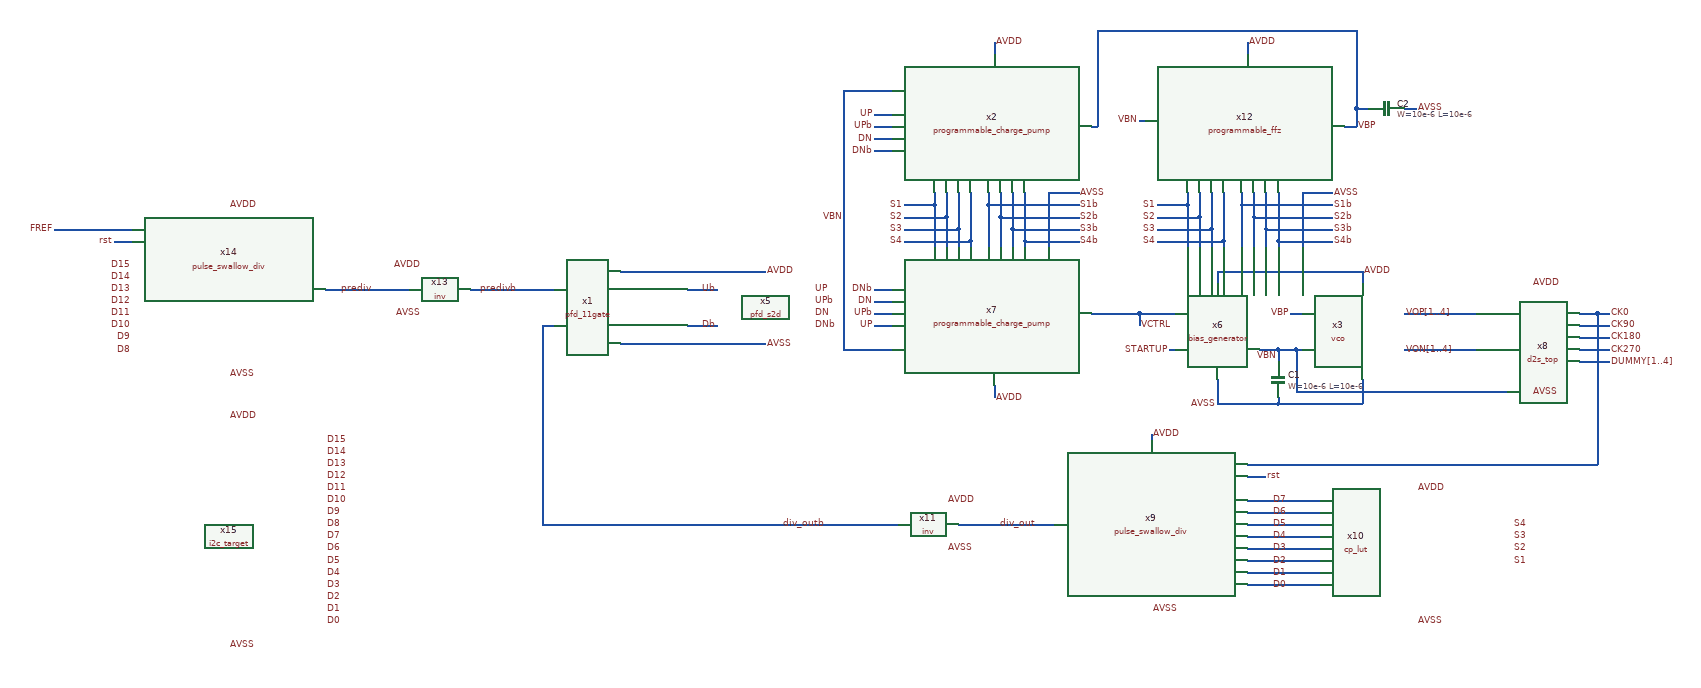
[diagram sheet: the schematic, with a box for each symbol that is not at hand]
v {xschem version=3.4.8RC file_version=1.3}
G {}
K {}
V {}
S {}
F {}
E {}
P 4 1 1360 -640 {}
N 1870 -610 1930 -610 {lab=VCTRL}
N 2130 -550 2140 -550 {lab=VBN}
N 2100 -550 2100 -530 {lab=VBN}
N 2240 -500 2240 -460 {lab=AVSS}
N 2100 -460 2240 -460 {lab=AVSS}
N 2000 -500 2000 -460 {lab=AVSS}
N 2240 -680 2240 -660 {lab=AVDD}
N 2000 -680 2000 -660 {lab=AVDD}
N 1920 -550 1930 -550 {lab=STARTUP}
N 2000 -680 2240 -680 {lab=AVDD}
N 1480 -790 1530 -790 {lab=S1}
N 1480 -770 1550 -770 {lab=S2}
N 1480 -750 1570 -750 {lab=S3}
N 1480 -730 1590 -730 {lab=S4}
N 1720 -810 1770 -810 {lab=AVSS}
N 1680 -730 1770 -730 {lab=S4b}
N 1660 -750 1770 -750 {lab=S3b}
N 1640 -770 1770 -770 {lab=S2b}
N 1620 -790 1770 -790 {lab=S1b}
N 1430 -880 1460 -880 {lab=DNb}
N 1430 -920 1460 -920 {lab=UPb}
N 1430 -900 1460 -900 {lab=DN}
N 1430 -940 1460 -940 {lab=UP}
N 1430 -650 1460 -650 {lab=DNb}
N 1430 -610 1460 -610 {lab=UPb}
N 1430 -630 1460 -630 {lab=DN}
N 1430 -590 1460 -590 {lab=UP}
N 1630 -1060 1630 -1040 {lab=AVDD}
N 1630 -490 1630 -470 {lab=AVDD}
N 1720 -810 1720 -720 {lab=AVSS}
N 1380 -980 1460 -980 {lab=VBN}
N 1380 -980 1380 -550 {lab=VBN}
N 1380 -550 1460 -550 {lab=VBN}
N 2230 -950 2230 -920 {lab=VBP}
N 1620 -790 1620 -720 {lab=S1b}
N 1640 -770 1640 -720 {lab=S2b}
N 1660 -750 1660 -720 {lab=S3b}
N 1680 -730 1680 -720 {lab=S4b}
N 1530 -790 1530 -720 {lab=S1}
N 1550 -770 1550 -720 {lab=S2}
N 1570 -750 1570 -720 {lab=S3}
N 1590 -730 1590 -720 {lab=S4}
N 1590 -810 1590 -730 {lab=S4}
N 1570 -810 1570 -750 {lab=S3}
N 1550 -810 1550 -770 {lab=S2}
N 1530 -810 1530 -790 {lab=S1}
N 1620 -810 1620 -790 {lab=S1b}
N 1640 -810 1640 -770 {lab=S2b}
N 1660 -810 1660 -750 {lab=S3b}
N 1680 -810 1680 -730 {lab=S4b}
N 2100 -470 2100 -460 {lab=AVSS}
N 2230 -950 2250 -950 {lab=VBP}
N 2310 -950 2330 -950 {lab=AVSS}
N 1900 -790 1950 -790 {lab=S1}
N 1900 -770 1970 -770 {lab=S2}
N 1900 -750 1990 -750 {lab=S3}
N 1900 -730 2010 -730 {lab=S4}
N 2140 -810 2190 -810 {lab=AVSS}
N 2100 -730 2190 -730 {lab=S4b}
N 2080 -750 2190 -750 {lab=S3b}
N 2060 -770 2190 -770 {lab=S2b}
N 2040 -790 2190 -790 {lab=S1b}
N 2140 -810 2140 -720 {lab=AVSS}
N 2040 -790 2040 -720 {lab=S1b}
N 2060 -770 2060 -720 {lab=S2b}
N 2080 -750 2080 -720 {lab=S3b}
N 2100 -730 2100 -720 {lab=S4b}
N 1950 -790 1950 -720 {lab=S1}
N 1970 -770 1970 -720 {lab=S2}
N 1990 -750 1990 -720 {lab=S3}
N 2010 -730 2010 -720 {lab=S4}
N 2010 -810 2010 -730 {lab=S4}
N 1990 -810 1990 -750 {lab=S3}
N 1970 -810 1970 -770 {lab=S2}
N 1950 -810 1950 -790 {lab=S1}
N 2040 -810 2040 -790 {lab=S1b}
N 2060 -810 2060 -770 {lab=S2b}
N 2080 -810 2080 -750 {lab=S3b}
N 2100 -810 2100 -730 {lab=S4b}
N 1870 -610 1870 -590 {lab=VCTRL}
N 2120 -610 2140 -610 {lab=VBP}
N 2210 -920 2230 -920 {lab=VBP}
N 1790 -920 1800 -920 {lab=VBP}
N 2230 -1080 2230 -950 {lab=VBP}
N 1800 -1080 2230 -1080 {lab=VBP}
N 1800 -1080 1800 -920 {lab=VBP}
N 2050 -1060 2050 -1040 {lab=AVDD}
N 1870 -930 1880 -930 {lab=VBN}
N 2310 -610 2430 -610 {lab=VOP[1..4]}
N 2310 -550 2430 -550 {lab=VON[1..4]}
N 2130 -480 2480 -480 {lab=VBN}
N 2130 -550 2130 -480 {lab=VBN}
N 2630 -610 2630 -360 {lab=CK0}
N 2600 -610 2630 -610 {lab=CK0}
N 2600 -590 2650 -590 {lab=CK90}
N 2630 -610 2650 -610 {lab=CK0}
N 2600 -570 2650 -570 {lab=CK180}
N 2600 -550 2650 -550 {lab=CK270}
N 2600 -530 2650 -530 {lab=DUMMY[1..4]}
N 2050 -360 2630 -360 {lab=CK0}
N 1790 -610 1870 -610 {lab=VCTRL}
N 2070 -550 2100 -550 {lab=VBN}
N 2000 -460 2100 -460 {lab=AVSS}
N 2100 -550 2130 -550 {lab=VBN}
N 1120 -650 1170 -650 {lab=Ub}
N 1120 -590 1170 -590 {lab=Db}
N 1010 -680 1250 -680 {lab=AVDD}
N 1010 -560 1250 -560 {lab=AVSS}
N 2050 -340 2080 -340 {lab=rst}
N 2050 -300 2170 -300 {lab=D7}
N 2050 -280 2170 -280 {lab=D6}
N 2050 -260 2170 -260 {lab=D5}
N 2050 -240 2170 -240 {lab=D4}
N 2050 -220 2170 -220 {lab=D3}
N 2050 -200 2170 -200 {lab=D2}
N 2050 -180 2170 -180 {lab=D1}
N 2050 -160 2170 -160 {lab=D0}
N 1570 -260 1600 -260 {lab=div_out}
N 70 -750 200 -750 {lab=FREF}
N 170 -730 200 -730 {lab=rst}
N 1890 -410 1890 -400 {lab=AVDD}
N 880 -590 880 -260 {lab=div_outb}
N 880 -590 900 -590 {lab=div_outb}
N 1600 -260 1730 -260 {lab=div_out}
N 880 -260 1470 -260 {lab=div_outb}
N 520 -650 660 -650 {lab=prediv}
N 760 -650 900 -650 {lab=predivb}
C {libs/core_analog/vco/vco.sym} 2240 -580 0 0 {name=x3}
C {libs/core_analog/bias_generator/bias_generator.sym} 2000 -580 0 0 {name=x6}
C {lab_pin.sym} 1380 -770 0 0 {name=p1 sig_type=std_logic lab=VBN}
C {lab_pin.sym} 2000 -460 0 0 {name=p9 sig_type=std_logic lab=AVSS}
C {lab_pin.sym} 1920 -550 0 0 {name=p11 sig_type=std_logic lab=STARTUP}
C {lab_pin.sym} 2310 -610 2 0 {name=p13 sig_type=std_logic lab=VOP[1..4]}
C {lab_pin.sym} 2310 -550 2 0 {name=p14 sig_type=std_logic lab=VON[1..4]}
C {lab_pin.sym} 2100 -540 0 0 {name=p38 sig_type=std_logic lab=VBN}
C {lab_pin.sym} 2120 -610 0 0 {name=p39 sig_type=std_logic lab=VBP}
C {lab_pin.sym} 1870 -590 0 1 {name=p42 sig_type=std_logic lab=VCTRL}
C {lab_pin.sym} 1630 -1060 0 1 {name=p43 sig_type=std_logic lab=AVDD}
C {libs/core_analog/programmable_charge_pump/programmable_charge_pump.sym} 1630 -920 0 0 {name=x2}
C {libs/core_analog/programmable_charge_pump/programmable_charge_pump.sym} 1630 -610 2 1 {name=x7}
C {lab_wire.sym} 1430 -940 0 0 {name=p47 sig_type=std_logic lab=UP}
C {lab_wire.sym} 1430 -900 0 0 {name=p48 sig_type=std_logic lab=DN}
C {lab_wire.sym} 1430 -880 0 0 {name=p49 sig_type=std_logic lab=DNb}
C {lab_wire.sym} 1430 -920 0 0 {name=p50 sig_type=std_logic lab=UPb}
C {lab_wire.sym} 1430 -590 2 1 {name=p51 sig_type=std_logic lab=UP}
C {lab_wire.sym} 1430 -630 2 1 {name=p52 sig_type=std_logic lab=DN}
C {lab_wire.sym} 1430 -650 2 1 {name=p53 sig_type=std_logic lab=DNb}
C {lab_wire.sym} 1430 -610 2 1 {name=p54 sig_type=std_logic lab=UPb}
C {lab_pin.sym} 1630 -470 2 0 {name=p2 sig_type=std_logic lab=AVDD}
C {lab_pin.sym} 1770 -810 0 1 {name=p46 sig_type=std_logic lab=AVSS}
C {lab_pin.sym} 1770 -790 2 0 {name=p55 sig_type=std_logic lab=S1b}
C {lab_pin.sym} 1770 -770 2 0 {name=p56 sig_type=std_logic lab=S2b}
C {lab_pin.sym} 1770 -750 2 0 {name=p57 sig_type=std_logic lab=S3b}
C {lab_pin.sym} 1770 -730 2 0 {name=p58 sig_type=std_logic lab=S4b}
C {lab_pin.sym} 1480 -790 2 1 {name=p59 sig_type=std_logic lab=S1}
C {lab_pin.sym} 1480 -770 2 1 {name=p60 sig_type=std_logic lab=S2}
C {lab_pin.sym} 1480 -750 2 1 {name=p61 sig_type=std_logic lab=S3}
C {lab_pin.sym} 1480 -730 2 1 {name=p62 sig_type=std_logic lab=S4}
C {lab_pin.sym} 2330 -950 2 0 {name=p45 sig_type=std_logic lab=AVSS}
C {libs/core_analog/programmable_ffz/programmable_ffz.sym} 2050 -930 0 0 {name=x12}
C {lab_pin.sym} 2190 -810 0 1 {name=p63 sig_type=std_logic lab=AVSS}
C {lab_pin.sym} 2190 -790 2 0 {name=p64 sig_type=std_logic lab=S1b}
C {lab_pin.sym} 2190 -770 2 0 {name=p65 sig_type=std_logic lab=S2b}
C {lab_pin.sym} 2190 -750 2 0 {name=p66 sig_type=std_logic lab=S3b}
C {lab_pin.sym} 2190 -730 2 0 {name=p67 sig_type=std_logic lab=S4b}
C {lab_pin.sym} 1900 -790 2 1 {name=p68 sig_type=std_logic lab=S1}
C {lab_pin.sym} 1900 -770 2 1 {name=p69 sig_type=std_logic lab=S2}
C {lab_pin.sym} 1900 -750 2 1 {name=p70 sig_type=std_logic lab=S3}
C {lab_pin.sym} 1900 -730 2 1 {name=p71 sig_type=std_logic lab=S4}
C {lab_pin.sym} 2230 -920 0 1 {name=p72 sig_type=std_logic lab=VBP}
C {lab_pin.sym} 2050 -1060 0 1 {name=p73 sig_type=std_logic lab=AVDD}
C {lab_pin.sym} 1870 -930 0 0 {name=p74 sig_type=std_logic lab=VBN}
C {libs/core_analog/d2s_top/d2s_top.sym} 2520 -580 0 0 {name=x8}
C {lab_pin.sym} 2520 -660 0 1 {name=p15 sig_type=std_logic lab=AVDD}
C {lab_pin.sym} 2520 -480 0 1 {name=p16 sig_type=std_logic lab=AVSS}
C {lab_pin.sym} 2650 -610 0 1 {name=p186 sig_type=std_logic lab=CK0}
C {lab_pin.sym} 2650 -590 0 1 {name=p187 sig_type=std_logic lab=CK90}
C {lab_pin.sym} 2650 -570 0 1 {name=p188 sig_type=std_logic lab=CK180}
C {lab_pin.sym} 2650 -550 0 1 {name=p189 sig_type=std_logic lab=CK270}
C {lab_pin.sym} 2650 -530 0 1 {name=p190 sig_type=std_logic lab=DUMMY[1..4]}
C {lab_pin.sym} 2240 -680 0 1 {name=p12 sig_type=std_logic lab=AVDD}
C {lab_wire.sym} 1330 -650 0 1 {name=p28 sig_type=std_logic lab=UP}
C {lab_wire.sym} 1330 -610 0 1 {name=p29 sig_type=std_logic lab=DN}
C {lab_wire.sym} 1330 -630 0 1 {name=p30 sig_type=std_logic lab=UPb}
C {lab_wire.sym} 1330 -590 0 1 {name=p31 sig_type=std_logic lab=DNb}
C {lab_wire.sym} 1700 -260 0 0 {name=p5 sig_type=std_logic lab=div_out
}
C {symbols/cap_mim_2f0fF.sym} 2100 -500 2 0 {name=C1
W=10e-6
L=10e-6
model=cap_mim_2f0fF
spiceprefix=X
m=50}
C {symbols/cap_mim_2f0fF.sym} 2280 -950 3 0 {name=C2
W=10e-6
L=10e-6
model=cap_mim_2f0fF
spiceprefix=X
m=50}
C {libs/core_analog/pfd/pfd_11gate.sym} 1010 -620 0 0 {name=x1}
C {lab_wire.sym} 1170 -650 0 0 {name=p6 sig_type=std_logic lab=Ub}
C {lab_wire.sym} 1170 -590 0 0 {name=p7 sig_type=std_logic lab=Db}
C {libs/core_analog/pfd_s2d/pfd_s2d.sym} 1250 -620 0 0 {name=x5}
C {lab_pin.sym} 1250 -680 2 0 {name=p85 sig_type=std_logic lab=AVDD}
C {lab_pin.sym} 1250 -560 0 1 {name=p86 sig_type=std_logic lab=AVSS}
C {libs/core_analog/pulse_swallow_div/src/pulse_swallow_div.sym} 1890 -260 0 1 {name=x9}
C {lab_pin.sym} 2080 -340 0 1 {name=p8 sig_type=std_logic lab=rst}
C {libs/core_analog/lut/cp_lut.sym} 2330 -140 0 0 {name=x10}
C {lab_pin.sym} 2330 -320 0 1 {name=p93 sig_type=std_logic lab=AVDD}
C {lab_pin.sym} 2490 -200 2 0 {name=p99 sig_type=std_logic lab=S1}
C {lab_pin.sym} 2490 -220 2 0 {name=p102 sig_type=std_logic lab=S2}
C {lab_pin.sym} 2490 -240 2 0 {name=p103 sig_type=std_logic lab=S3}
C {lab_pin.sym} 2490 -260 2 0 {name=p104 sig_type=std_logic lab=S4}
C {lab_pin.sym} 2090 -300 0 1 {name=p10 sig_type=std_logic lab=D7}
C {lab_pin.sym} 2090 -280 0 1 {name=p17 sig_type=std_logic lab=D6}
C {lab_pin.sym} 2090 -260 0 1 {name=p18 sig_type=std_logic lab=D5}
C {lab_pin.sym} 2090 -240 0 1 {name=p19 sig_type=std_logic lab=D4}
C {lab_pin.sym} 2090 -220 0 1 {name=p110 sig_type=std_logic lab=D3}
C {lab_pin.sym} 2090 -200 0 1 {name=p111 sig_type=std_logic lab=D2}
C {lab_pin.sym} 2090 -180 0 1 {name=p112 sig_type=std_logic lab=D1}
C {lab_pin.sym} 2090 -160 0 1 {name=p113 sig_type=std_logic lab=D0}
C {libs/core_analog/inv/inv.sym} 1530 -260 0 1 {name=x11}
C {libs/core_analog/inv/inv.sym} 700 -650 0 0 {name=x13}
C {lab_pin.sym} 1550 -300 2 0 {name=p20 sig_type=std_logic lab=AVDD}
C {lab_pin.sym} 2330 -100 0 1 {name=p21 sig_type=std_logic lab=AVSS}
C {lab_pin.sym} 1890 -120 0 1 {name=p22 sig_type=std_logic lab=AVSS}
C {lab_pin.sym} 1550 -220 0 1 {name=p23 sig_type=std_logic lab=AVSS}
C {lab_pin.sym} 680 -690 2 1 {name=p24 sig_type=std_logic lab=AVDD}
C {lab_pin.sym} 680 -610 0 0 {name=p25 sig_type=std_logic lab=AVSS}
C {libs/core_analog/pulse_swallow_div/src/pulse_swallow_div.sym} 360 -650 0 0 {name=x14}
C {libs/core_analog/I2C/i2c_target.sym} 360 -240 0 0 {name=x15}
C {lab_pin.sym} 360 -790 2 0 {name=p26 sig_type=std_logic lab=AVDD}
C {lab_pin.sym} 360 -510 0 1 {name=p27 sig_type=std_logic lab=AVSS}
C {lab_pin.sym} 170 -730 0 0 {name=p32 sig_type=std_logic lab=rst}
C {lab_pin.sym} 520 -240 0 1 {name=p33 sig_type=std_logic lab=D7}
C {lab_pin.sym} 520 -220 0 1 {name=p34 sig_type=std_logic lab=D6}
C {lab_pin.sym} 520 -200 0 1 {name=p35 sig_type=std_logic lab=D5}
C {lab_pin.sym} 520 -180 0 1 {name=p36 sig_type=std_logic lab=D4}
C {lab_pin.sym} 520 -160 0 1 {name=p37 sig_type=std_logic lab=D3}
C {lab_pin.sym} 520 -140 0 1 {name=p40 sig_type=std_logic lab=D2}
C {lab_pin.sym} 520 -120 0 1 {name=p41 sig_type=std_logic lab=D1}
C {lab_pin.sym} 520 -100 0 1 {name=p44 sig_type=std_logic lab=D0}
C {lab_pin.sym} 520 -400 0 1 {name=p75 sig_type=std_logic lab=D15}
C {lab_pin.sym} 520 -380 0 1 {name=p76 sig_type=std_logic lab=D14}
C {lab_pin.sym} 520 -360 0 1 {name=p77 sig_type=std_logic lab=D13}
C {lab_pin.sym} 520 -340 0 1 {name=p78 sig_type=std_logic lab=D12}
C {lab_pin.sym} 520 -320 0 1 {name=p79 sig_type=std_logic lab=D11}
C {lab_pin.sym} 520 -300 0 1 {name=p80 sig_type=std_logic lab=D10}
C {lab_pin.sym} 520 -280 0 1 {name=p81 sig_type=std_logic lab=D9}
C {lab_pin.sym} 520 -260 0 1 {name=p82 sig_type=std_logic lab=D8}
C {lab_pin.sym} 360 -60 0 1 {name=p83 sig_type=std_logic lab=AVSS}
C {lab_pin.sym} 360 -440 2 0 {name=p84 sig_type=std_logic lab=AVDD}
C {lab_pin.sym} 200 -690 0 0 {name=p87 sig_type=std_logic lab=D15}
C {lab_pin.sym} 200 -670 0 0 {name=p88 sig_type=std_logic lab=D14}
C {lab_pin.sym} 200 -650 0 0 {name=p89 sig_type=std_logic lab=D13}
C {lab_pin.sym} 200 -630 0 0 {name=p90 sig_type=std_logic lab=D12}
C {lab_pin.sym} 200 -610 0 0 {name=p91 sig_type=std_logic lab=D11}
C {lab_pin.sym} 200 -590 0 0 {name=p92 sig_type=std_logic lab=D10}
C {lab_pin.sym} 200 -570 0 0 {name=p94 sig_type=std_logic lab=D9}
C {lab_pin.sym} 200 -550 0 0 {name=p95 sig_type=std_logic lab=D8}
C {lab_pin.sym} 70 -750 0 0 {name=p96 sig_type=std_logic lab=FREF}
C {lab_pin.sym} 1890 -410 2 0 {name=p3 sig_type=std_logic lab=AVDD}
C {lab_wire.sym} 1350 -260 0 0 {name=p97 sig_type=std_logic lab=div_outb
}
C {lab_wire.sym} 600 -650 0 0 {name=p4 sig_type=std_logic lab=prediv
}
C {lab_wire.sym} 840 -650 0 0 {name=p98 sig_type=std_logic lab=predivb
}
